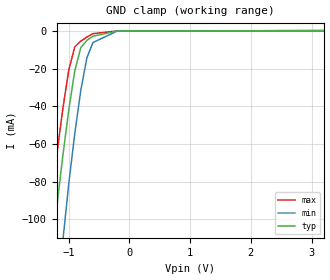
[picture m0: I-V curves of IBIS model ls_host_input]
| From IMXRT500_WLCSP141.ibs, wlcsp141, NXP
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[Model] ls_host_input
|   Model ls_host_input
| Library cells for typ/min/max conditions are connected as defined below:
|  pad_usbdp - External Pad
|  d_dmpulldn - vddd
|  d_dppulldn - vddd
|  d_sw1_neg - gnda
|  d_sw1_pos - gnda
|  d_sw2_neg - gnda
|  d_sw2_pos - gnda
|  gnda - gnda
|  pad_usb_vss - pad_usb_vss
|  usb2_reg_tx_fs_hiz - vddd
|  usb2_reg_tx_hs_term - gnda
|  usb2_reg_tx_hs_xcvr - vddd
|  usb2_reg_tx_ls_en - gnda
|  vddb - vddb
|  vddd - vddd
| All other pins connected to ground
Model_type Input
Vinl =   0.800V
Vinh =   2.000V
C_comp   2.8431pF   2.6338pF   3.0727pF
[Temperature Range]   27.0000   0.1250k   -40.0000
[Voltage Range]   3.1500V   3.0000V   3.3000V
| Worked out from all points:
|   GND clamp passes 1 mA (typ) near -0.49 V on its own axis
[GND_clamp]
|Voltage   I(typ)   I(min)   I(max)
-3.3V     -1.77A     -1.861A    -1.685A
-1.4V     -157.5mA   -242mA     -123.3mA
-1.3V     -124.5mA   -192.1mA   -93.95mA
-1.2V     -94.77mA   -149.4mA   -66.85mA
-1.1V     -67.27mA   -112.8mA   -42.22mA
-1V       -42.3mA    -81.55mA   -20.98mA
-900mV    -21.24mA   -54.58mA   -8.478mA
-800mV    -8.783mA   -31.46mA   -5.373mA
-700mV    -5.002mA   -14.24mA   -3.221mA
-600mV    -2.797mA   -6.151mA   -1.432mA
-200mV    -10.86uA   -44.63uA   -10.07uA
3.2V      167.9uA    211.3uA    161.1uA
